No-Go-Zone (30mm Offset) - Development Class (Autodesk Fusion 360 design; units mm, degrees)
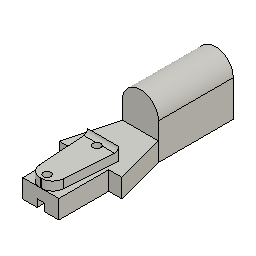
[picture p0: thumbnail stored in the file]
description: Part Number
part number: No_Go_Zone Including Halo_Platform Assembled With 30mm Offset
base_feature "Base Feature"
